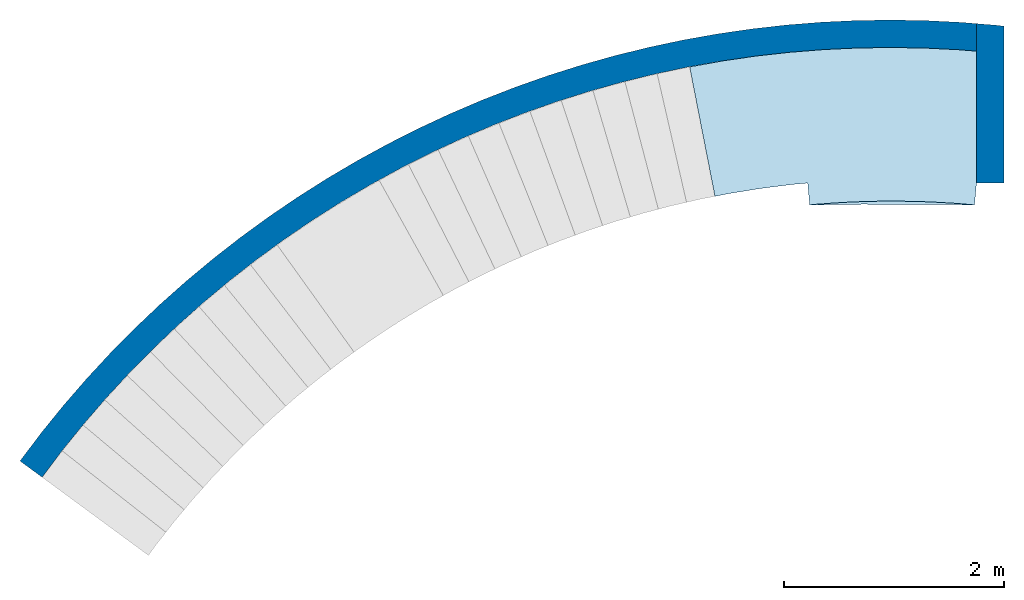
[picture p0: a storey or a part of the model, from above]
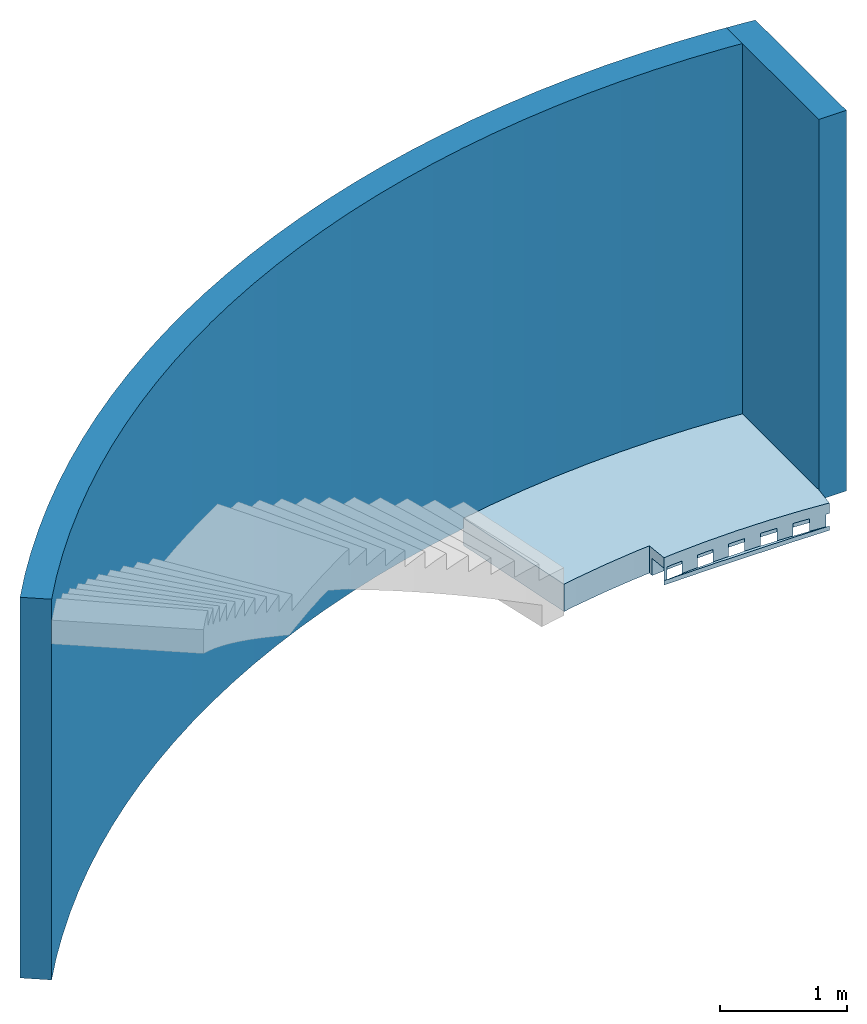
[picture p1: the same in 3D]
Properties of the parts of a building model (IFC4)

# File
Description: ViewDefinition [ReferenceView_V1.2], ExchangeRequirement [Architecture], Option [Elements to export: Visible elements (on all stories)], Option [Partial Structure Display: Entire Model], Option [IFC Domain: All], Option [Structural Function: All Elements], Option [Convert Grid elements: On], Option [Convert IFC Annotations and Archicad 2D elements: Off], Option [Convert 2D symbols of Doors and Windows: Off], Option [Export geometries that Participates in Collision Detection only: On], Option [Split complex elements: Off], Option [Material Preservation: Explode where necessary], Option [IFC Model position: Survey Point and Project Origin], Option [Curtain Wall export mode: Single Element], Option [Railing export mode: Single Element], Option [Stair export mode: Single Element], Option [Properties To Export: All properties], Option [Space containment: On], Option [IFC Domain For Space Containment: All], Option [Geometry to type objects: Off], Option [Element Properties: Off], Option [Building Material Properties: Off], Option [Element Parameters: Off], Option [Component Parameters: Off], Option [IFC Base Quantities: On], Option [Door Window Parameters: On], Option [IFC Space boundaries: On], Option [Archicad Zone Categories as IFC Space classification data: Off], Option [Element Classifications: Off]
File name: C:\Users\micel\OneDrive\Dokumenty\ŠKOLA\!!4.LS!!\BAKALÁŘKA\Publikace\Nová složka\LES24-PST-XX-M3-Vnejsi_konstrukce.ifc
Time: 2024-05-22T15:32:13
Author: Architect
Organization: Building Designer Office
Written by: DDS_IFC v3.0
Made in: IFC file generated by Graphisoft Archicad 27.0.0 CZE FULL Windows version (IFC add-on version: 3001 CZE FULL).
Authorization: The authorising person

# IfcProject, Univerzitní lezecké centrum
Description: BIM projekt - bakalářská práce

# IfcSite, Exteriér
RefLatitude: 50, 1, 18, 339575; RefLongitude: 15, 46, 11, 568244; RefElevation: 221783 mm
Qto_SiteBaseQuantities - GrossPerimeter: 0 mm; GrossArea: 3562 m2

# IfcBuilding, Univerzitní lezecké centrum
Qto_BuildingBaseQuantities - GrossFloorArea: 0 m2

# IfcBuildingStorey (2)
In: Univerzitní lezecké centrum
Qto_BuildingStoreyBaseQuantities - GrossFloorArea: 0 m2
Name | Elevation (mm) | NetHeight (mm) = GrossHeight (mm)
1.PP | -3350 | 3350
1.NP | 0 | 3200

# IfcSlab: !Okapový chodník/Terasa/chodník 312 (2)
Type - PredefinedType: FLOOR
Material: Betonová dlažba zámková, Štěrk - frakce 4/8, Štěrk - frakce 8/16, Geotextilie 300 g/m2
Pset_SlabCommon - Status: EXISTING
Qto_SlabBaseQuantities - Width: 312 mm; Betonová dlažba zámková, Width: 60 mm; Štěrk - frakce 4/8, Width: 40 mm; Štěrk - frakce 8/16, Width: 160 mm; Geotextilie 300 g/m2, Width: 2 mm
Pset_ManufacturerOccurrence - AcquisitionDate: DD.MM.RRRR
Name | In | Perimeter (mm) | GrossArea (m2) | NetArea (m2) | GrossVolume (m3) | NetVolume (m3)
 | 1.PP | 7775.63 | 3.33915 | 3.30758 | 0.99369 | 0.983842
 | 1.NP | 14640 | 9.25963 | 9.25963 | 2.889 | 2.889 | Pset_SlabCommon - LoadBearing: yes

# IfcStair: Typ schodiště, SCH016
In: 1.PP
Material: Beton vyztužený (3)
Pset_StairCommon - NumberOfRiser: 21; NumberOfTreads: 21; RiserHeight: 159.524 mm; WalkingLineOffset: 6692.38 mm; RequiredHeadroom: 2200 mm; Status: EXISTING
Pset_ManufacturerOccurrence - AcquisitionDate: DD.MM.RRRR

# IfcWall: Beton vyztužený - oplocení 200 (10)
In: 1.NP
Material: Beton vyztužený - oplocení
Pset_WallCommon - Status: EXISTING; LoadBearing: yes
Pset_ManufacturerOccurrence - AcquisitionDate: DD.MM.RRRR
Qto_WallBaseQuantities - Width: 200 mm; Beton vyztužený - oplocení, Width: 200 mm
Name | Length (mm) | Height (mm) | GrossFootprintArea (m2) = NetFootprintArea (m2) | GrossSideArea (m2) = NetSideArea (m2) | GrossVolume (m3) = NetVolume (m3)
Z050 | 21007.5 | 1200 | 4.2015 | 25.209 | 5.0418
Z051 | 12793.5 | 1200 | 1.70189 | 10.2113 | 2.04227
Z050 | 10756.4 | 1200 | 3.00808 | 18.0485 | 3.6097
Z052 | 7664.65 | 1200 | 1.55293 | 9.31758 | 1.86352
Z053 | 67989.1 | 1200 | 13.5778 | 81.4669 | 16.2934
Z050 | 21007.5 | 2200 | 4.2015 | 46.2165 | 9.24331
Z050 | 10756.4 | 2200 | 3.00808 | 33.0889 | 6.61778
Z051 | 12793.5 | 2200 | 1.70189 | 18.7208 | 3.74416
Z052 | 7664.65 | 2200 | 1.55293 | 17.0822 | 3.41645
Z053 | 67989.1 | 2200 | 13.5778 | 149.356 | 29.8712

# IfcWall: Betonové tvárnice - nosné 200
In: 1.NP
Material: Betonové tvárnice - nosné
Pset_WallCommon - Status: EXISTING; LoadBearing: yes
Pset_ManufacturerOccurrence - AcquisitionDate: DD.MM.RRRR
Qto_WallBaseQuantities - Length: 5943.82 mm; Height: 2200 mm; Width: 200 mm; GrossFootprintArea: 1.13875 m2; NetFootprintArea: 1.13875 m2; GrossSideArea: 12.5263 m2; NetSideArea: 12.5263 m2; GrossVolume: 2.50526 m3; NetVolume: 2.50526 m3; Betonové tvárnice - nosné, Width: 200 mm

# IfcWall: Betonové tvárnice - nosné 250 (4)
Material: Betonové tvárnice - nosné
Pset_WallCommon - Status: EXISTING; LoadBearing: yes
Pset_ManufacturerOccurrence - AcquisitionDate: DD.MM.RRRR
Qto_WallBaseQuantities - Width: 250 mm; Betonové tvárnice - nosné, Width: 250 mm
Name | In | Length (mm) | Height (mm) | GrossFootprintArea (m2) = NetFootprintArea (m2) | GrossSideArea (m2) = NetSideArea (m2) | GrossVolume (m3) = NetVolume (m3)
 | 1.PP | 1313.75 | 3650 | 0.36005 | 5.25369 | 1.31418
 | 1.PP | 10005.3 | 3650 | 2.47015 | 36.0643 | 9.01605
 | 1.NP | 1792.65 | 2200 | 0.473167 | 4.16387 | 1.04097
 | 1.NP | 1662.47 | 2200 | 0.440624 | 3.87749 | 0.969372
